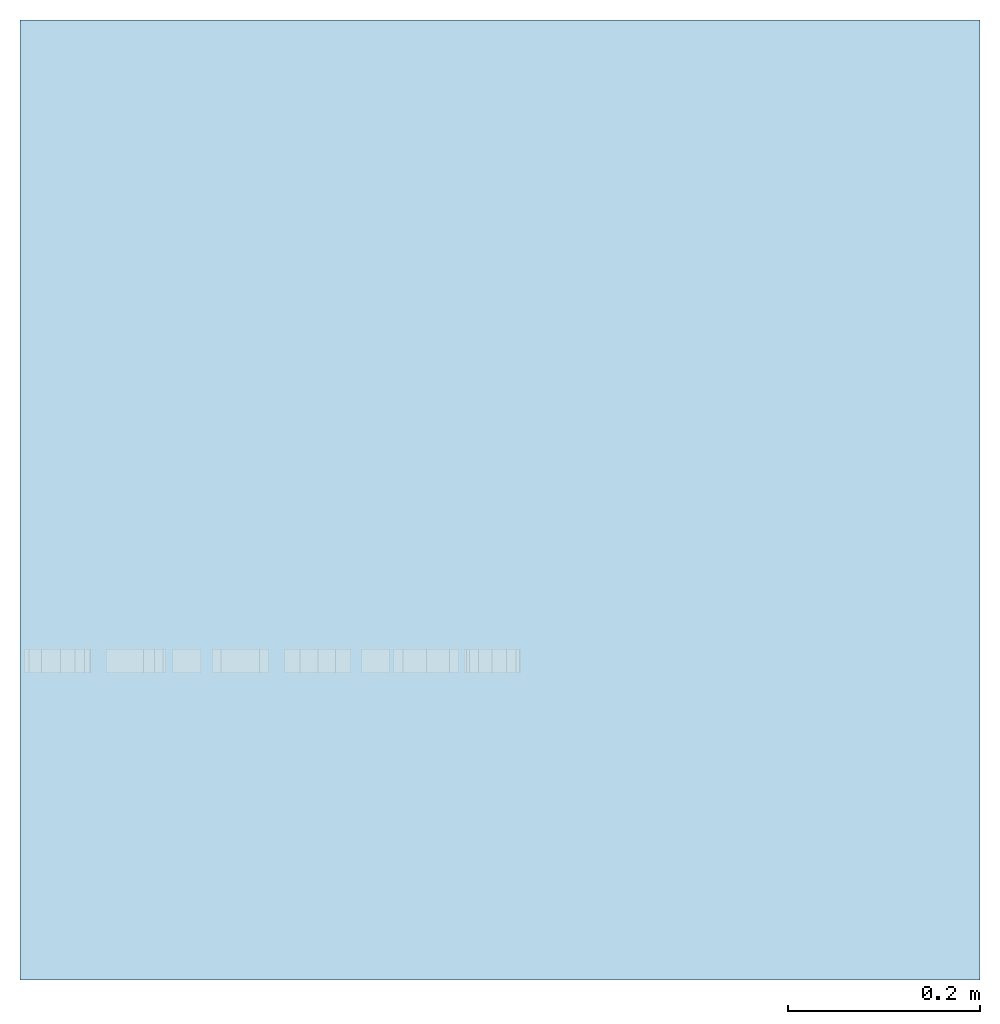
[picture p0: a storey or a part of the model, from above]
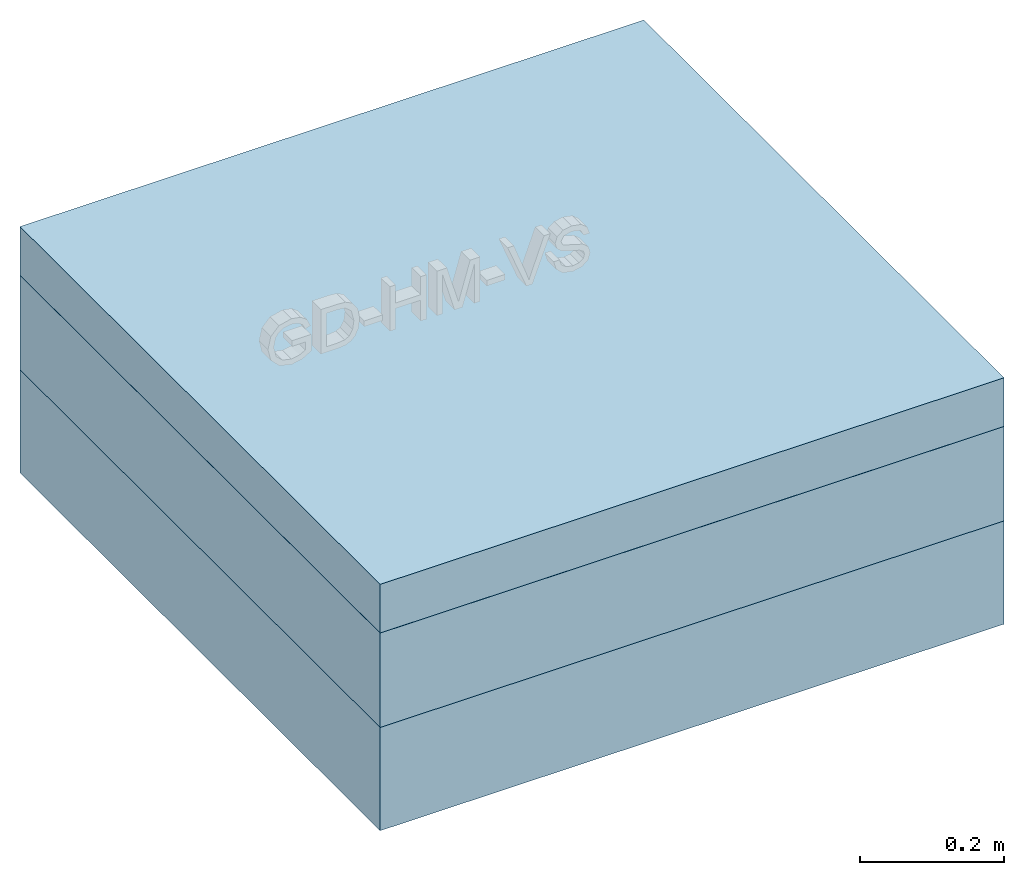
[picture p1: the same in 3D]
Properties of the parts of a building model (IFC4)

# File
Description: ViewDefinition [ReferenceView_V1.2], RevitIdentifiers [VersionGUID: 71a4b502-a2af-483b-88dc-542061cd4702, NumberOfSaves: 1], CoordinateReference [CoordinateBase: Gemeinsam genutzte Koordinaten], ExchangeRequirement [Architecture]
File name: 2018_01
Time: 2023-06-27T16:00:12+01:00
Written by: ODA SDAI 23.12
Made in: Autodesk Revit 24.0.5.432 (DEU) - IFC 24.0.5.432

# IfcProject, 2018_01
Phase: Projekt Status

# IfcSite, Default
RefLatitude: 48, 8, 15, 359802; RefLongitude: 11, 34, 47, 783432; RefElevation: 0 m
Pset_SiteCommon - Reference: Projektinformationen

# IfcBuildingElementProxy: Modelltext:075mm Arial, Modelltext:075mm Arial:2510192
In: Default
Type - Pset_BuildingElementProxyCommon - IsExternal: no
Pset_BuildingElementProxyCommon - Reference: 075mm Arial
Pset_EnvironmentalImpactIndicators - Reference: 075mm Arial
Qto_BuildingElementProxyQuantities - NetSurfaceArea: 0.0947139 m2; NetVolume: 0.000309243 m3

# IfcElementAssembly: Geschossdecken Baugruppe:fbimSg_Slab_bc_WOD_vis_at_NTR_natuREbuilt_GD-HM-VS_GK3_42cm, Geschossdecken Baugruppe:fbimSg_Slab_bc_WOD_vis_at_NTR_natuREbuilt_GD-HM-VS_GK3_42cm:2510214
In: Default
PredefinedType: USERDEFINED; Material: fbim_14100590_AT_001_Luftschicht, fbim_14101045_AT_034_Mineralwolle_Daemmfilz, fbim_14101050_AT_Mineralwolldaemmung, fbim_16101505_AT_Gipsfaserplatte
Pset_ElementAssemblyCommon - Reference: fbimSg_Slab_bc_WOD_vis_at_NTR_natuREbuilt_GD-HM-VS_GK3_42cm; sets with these values: 2

# IfcSlab: Geschossdecke:fbimSg_Floor_dp_INS_vis_at_NTR_natuREbuilt_MhD_GK3_o_17,5cm, Geschossdecke:fbimSg_Floor_dp_INS_vis_at_NTR_natuREbuilt_MhD_GK3_o_17,5cm:2510195
In: Default
Type - PredefinedType: FLOOR; Material: fbim_14100590_AT_001_Luftschicht, fbim_14101045_AT_034_Mineralwolle_Daemmfilz, fbim_14101050_AT_Mineralwolldaemmung, fbim_16101505_AT_Gipsfaserplatte
Type - Pset_SlabCommon - IsExternal: no
Pset_EnvironmentalImpactIndicators - Reference: fbimSg_Floor_dp_INS_vis_at_NTR_natuREbuilt_MhD_GK3_o_17,5cm; sets with these values: 2
Pset_SlabCommon - Reference: fbimSg_Floor_dp_INS_vis_at_NTR_natuREbuilt_MhD_GK3_o_17,5cm; PitchAngle: 0 deg; LoadBearing: no
Qto_SlabBaseQuantities - fbim_14100590_AT_001_Luftschicht, Width: 0.01 m; fbim_14101045_AT_034_Mineralwolle_Daemmfilz, Width: 0.02 m; fbim_14101050_AT_Mineralwolldaemmung, Width: 0.04 m; fbim_16101505_AT_Gipsfaserplatte, Width: 0.0125 m; Width: 0.0825 m; Length: 1 m; Depth: 0.0125 m; Perimeter: 4 m; GrossArea: 1 m2; GrossVolume: 0.0125 m3; NetVolume: 0.0825 m3

# IfcSlab: Geschossdecke:fbimSg_Slab_dp_DRW_vis_at_NTR_natuREbuilt_MhD_GK3_u_6cm, Geschossdecke:fbimSg_Slab_dp_DRW_vis_at_NTR_natuREbuilt_MhD_GK3_u_6cm:2510209
In: Default
Type - PredefinedType: FLOOR; Material: fbim_18108010_AT_015_Parkettboden, fbim_16051005_AT_225_Estrichbeton_E225, fbim_14104050_AT_035_MW-Trittschalldaemmplatte, fbim_10053020_AT_024_Splitt_2-4
Type - Pset_SlabCommon - IsExternal: no
Pset_EnvironmentalImpactIndicators - Reference: fbimSg_Slab_dp_DRW_vis_at_NTR_natuREbuilt_MhD_GK3_u_6cm; sets with these values: 2
Pset_SlabCommon - PitchAngle: 0 deg; LoadBearing: no; Reference: fbimSg_Slab_dp_DRW_vis_at_NTR_natuREbuilt_MhD_GK3_u_6cm
Qto_SlabBaseQuantities - fbim_18108010_AT_015_Parkettboden, Width: 0.015 m; fbim_16051005_AT_225_Estrichbeton_E225, Width: 0.07 m; fbim_14104050_AT_035_MW-Trittschalldaemmplatte, Width: 0.03 m; fbim_10053020_AT_024_Splitt_2-4, Width: 0.06 m; Width: 0.175 m; Length: 1 m; Depth: 0.06 m; Perimeter: 4 m; GrossArea: 1 m2; GrossVolume: 0.06 m3; NetVolume: 0.175 m3

# IfcSlab: Geschossdecke:fbimSg_Slab_sb_WOD_vis_at_NTR_natuREbuilt_MhD_GK3_k_16cm, Geschossdecke:fbimSg_Slab_sb_WOD_vis_at_NTR_natuREbuilt_MhD_GK3_k_16cm:2510202
In: Default
Type - PredefinedType: FLOOR; Material: fbim_AT_KLH_Massivholz
Type - Pset_SlabCommon - IsExternal: no
Pset_EnvironmentalImpactIndicators - Reference: fbimSg_Slab_sb_WOD_vis_at_NTR_natuREbuilt_MhD_GK3_k_16cm; sets with these values: 2
Pset_SlabCommon - PitchAngle: 0 deg; LoadBearing: no; Reference: fbimSg_Slab_sb_WOD_vis_at_NTR_natuREbuilt_MhD_GK3_k_16cm
Qto_SlabBaseQuantities - Width: 1 m; Length: 1 m; Depth: 0.16 m; Perimeter: 4 m; GrossArea: 1 m2; GrossVolume: 0.16 m3; NetVolume: 0.16 m3
